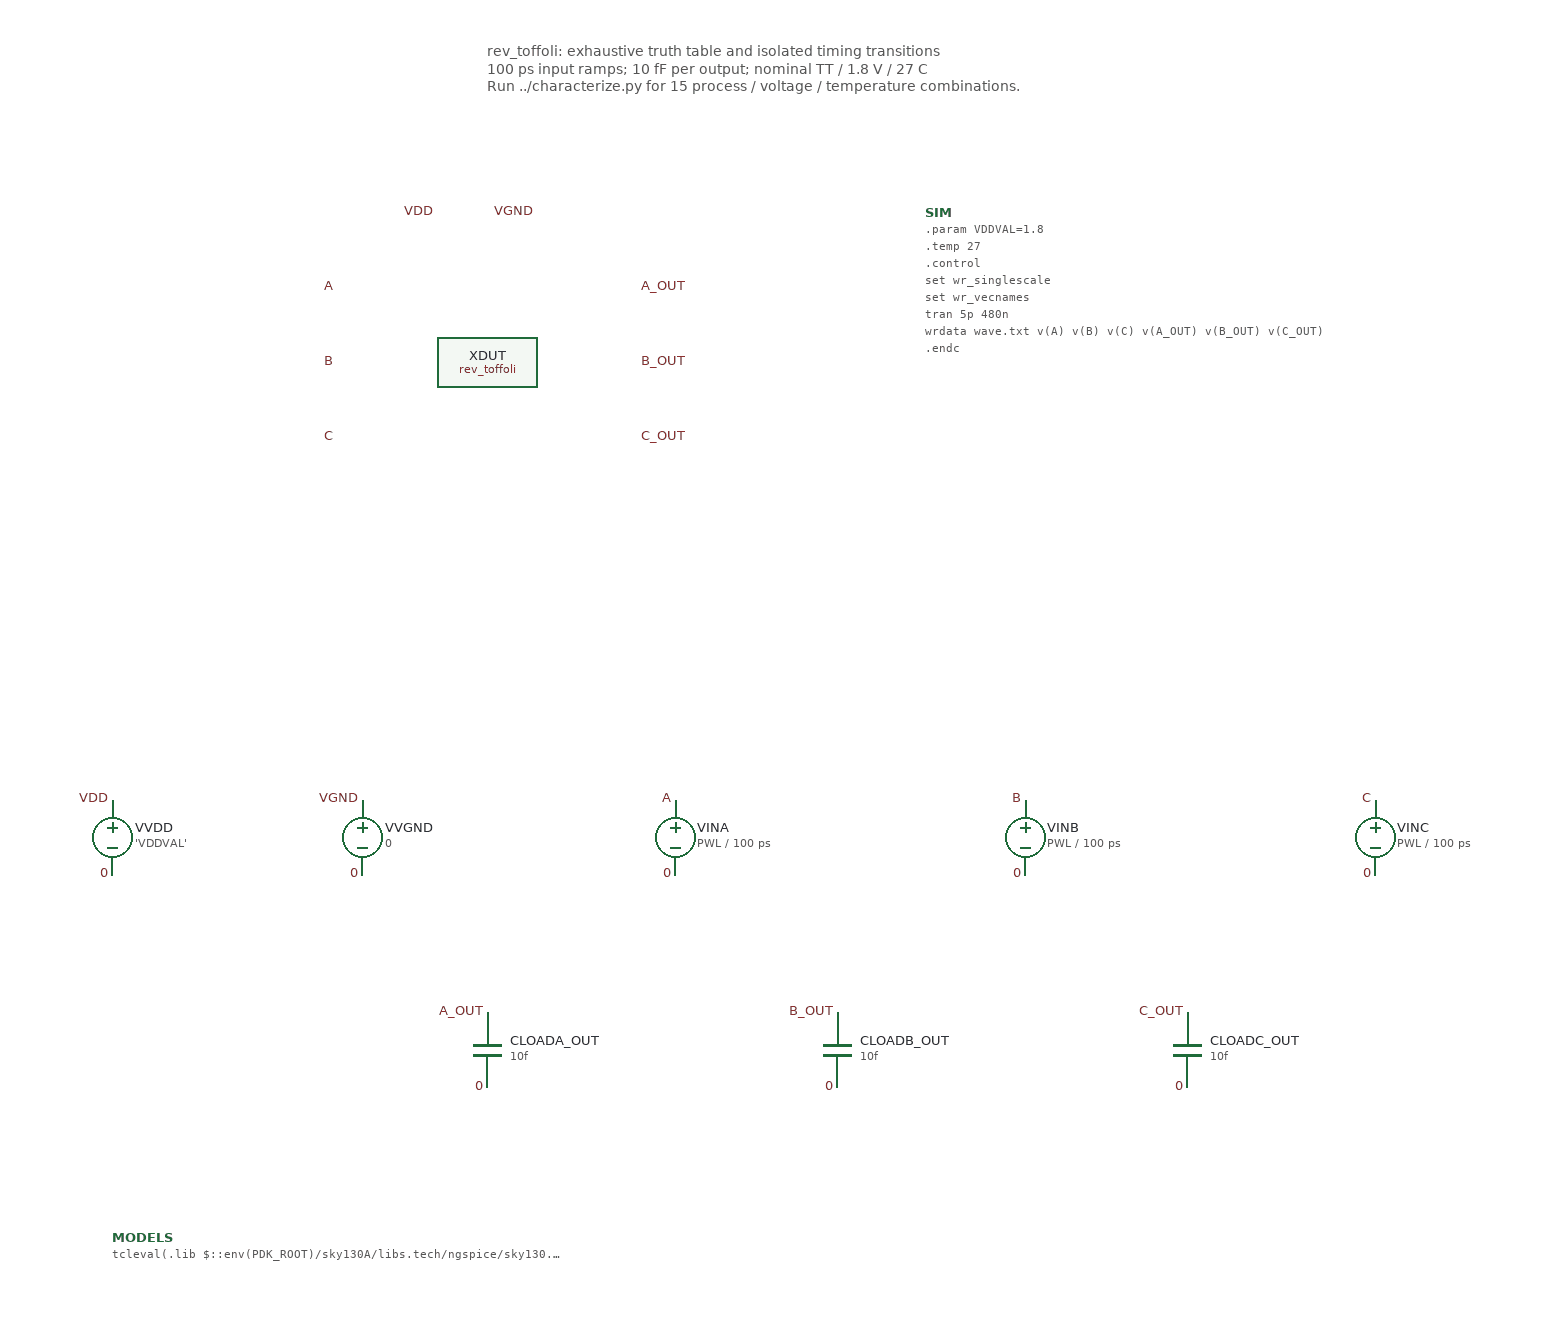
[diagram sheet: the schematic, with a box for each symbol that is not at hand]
v {xschem version=3.4.8RC file_version=1.3}
G {}
K {}
V {}
S {}
E {}
T {rev_toffoli: exhaustive truth table and isolated timing transitions
100 ps input ramps; 10 fF per output; nominal TT / 1.8 V / 27 C
Run ../characterize.py for 15 process / voltage / temperature combinations.} 0 -260 0 0 0.35 0.35 {}
C {rev_toffoli.sym} 0 0 0 0 {name=XDUT}
C {lab_pin.sym} -40 -120 0 0 {name=l-40_-120 sig_type=std_logic lab=VDD}
C {lab_pin.sym} 40 -120 0 0 {name=l40_-120 sig_type=std_logic lab=VGND}
C {lab_pin.sym} -120 -60 0 0 {name=l-120_-60 sig_type=std_logic lab=A}
C {lab_pin.sym} -120 0 0 0 {name=l-120_0 sig_type=std_logic lab=B}
C {lab_pin.sym} -120 60 0 0 {name=l-120_60 sig_type=std_logic lab=C}
C {lab_pin.sym} 120 -60 0 1 {name=l120_-60 lab=A_OUT}
C {lab_pin.sym} 120 0 0 1 {name=l120_0 lab=B_OUT}
C {lab_pin.sym} 120 60 0 1 {name=l120_60 lab=C_OUT}
C {vsource.sym} -300 380 0 0 {name=VVDD value="'VDDVAL'"}
C {lab_pin.sym} -300 350 0 0 {name=l-300_350 sig_type=std_logic lab=VDD}
C {lab_pin.sym} -300 410 0 0 {name=l-300_410 sig_type=std_logic lab=0}
C {vsource.sym} -100 380 0 0 {name=VVGND value="0"}
C {lab_pin.sym} -100 350 0 0 {name=l-100_350 sig_type=std_logic lab=VGND}
C {lab_pin.sym} -100 410 0 0 {name=l-100_410 sig_type=std_logic lab=0}
C {vsource.sym} 150 380 0 0 {name=VINA value="PWL / 100 ps" format="@name @pinlist @stimulus" stimulus="PWL(
+ 0n 'VDDVAL*0'
+ 10n 'VDDVAL*0'
+ 10.1n 'VDDVAL*1'
+ 20n 'VDDVAL*1'
+ 20.1n 'VDDVAL*0'
+ 30n 'VDDVAL*0'
+ 30.1n 'VDDVAL*0'
+ 40n 'VDDVAL*0'
+ 40.1n 'VDDVAL*0'
+ 50n 'VDDVAL*0'
+ 50.1n 'VDDVAL*0'
+ 60n 'VDDVAL*0'
+ 60.1n 'VDDVAL*0'
+ 70n 'VDDVAL*0'
+ 70.1n 'VDDVAL*1'
+ 80n 'VDDVAL*1'
+ 80.1n 'VDDVAL*0'
+ 90n 'VDDVAL*0'
+ 90.1n 'VDDVAL*0'
+ 100n 'VDDVAL*0'
+ 100.1n 'VDDVAL*0'
+ 110n 'VDDVAL*0'
+ 110.1n 'VDDVAL*0'
+ 120n 'VDDVAL*0'
+ 120.1n 'VDDVAL*0'
+ 130n 'VDDVAL*0'
+ 130.1n 'VDDVAL*1'
+ 140n 'VDDVAL*1'
+ 140.1n 'VDDVAL*0'
+ 150n 'VDDVAL*0'
+ 150.1n 'VDDVAL*0'
+ 160n 'VDDVAL*0'
+ 160.1n 'VDDVAL*0'
+ 170n 'VDDVAL*0'
+ 170.1n 'VDDVAL*0'
+ 180n 'VDDVAL*0'
+ 180.1n 'VDDVAL*0'
+ 190n 'VDDVAL*0'
+ 190.1n 'VDDVAL*1'
+ 200n 'VDDVAL*1'
+ 200.1n 'VDDVAL*0'
+ 210n 'VDDVAL*0'
+ 210.1n 'VDDVAL*0'
+ 220n 'VDDVAL*0'
+ 220.1n 'VDDVAL*0'
+ 230n 'VDDVAL*0'
+ 230.1n 'VDDVAL*0'
+ 240n 'VDDVAL*0'
+ 240.1n 'VDDVAL*1'
+ 250n 'VDDVAL*1'
+ 250.1n 'VDDVAL*0'
+ 260n 'VDDVAL*0'
+ 260.1n 'VDDVAL*1'
+ 270n 'VDDVAL*1'
+ 270.1n 'VDDVAL*1'
+ 280n 'VDDVAL*1'
+ 280.1n 'VDDVAL*1'
+ 290n 'VDDVAL*1'
+ 290.1n 'VDDVAL*1'
+ 300n 'VDDVAL*1'
+ 300.1n 'VDDVAL*1'
+ 310n 'VDDVAL*1'
+ 310.1n 'VDDVAL*0'
+ 320n 'VDDVAL*0'
+ 320.1n 'VDDVAL*1'
+ 330n 'VDDVAL*1'
+ 330.1n 'VDDVAL*1'
+ 340n 'VDDVAL*1'
+ 340.1n 'VDDVAL*1'
+ 350n 'VDDVAL*1'
+ 350.1n 'VDDVAL*1'
+ 360n 'VDDVAL*1'
+ 360.1n 'VDDVAL*1'
+ 370n 'VDDVAL*1'
+ 370.1n 'VDDVAL*0'
+ 380n 'VDDVAL*0'
+ 380.1n 'VDDVAL*1'
+ 390n 'VDDVAL*1'
+ 390.1n 'VDDVAL*1'
+ 400n 'VDDVAL*1'
+ 400.1n 'VDDVAL*1'
+ 410n 'VDDVAL*1'
+ 410.1n 'VDDVAL*1'
+ 420n 'VDDVAL*1'
+ 420.1n 'VDDVAL*1'
+ 430n 'VDDVAL*1'
+ 430.1n 'VDDVAL*0'
+ 440n 'VDDVAL*0'
+ 440.1n 'VDDVAL*1'
+ 450n 'VDDVAL*1'
+ 450.1n 'VDDVAL*1'
+ 460n 'VDDVAL*1'
+ 460.1n 'VDDVAL*1'
+ 470n 'VDDVAL*1'
+ 470.1n 'VDDVAL*1')"}
C {lab_pin.sym} 150 350 0 0 {name=l150_350 sig_type=std_logic lab=A}
C {lab_pin.sym} 150 410 0 0 {name=l150_410 sig_type=std_logic lab=0}
C {vsource.sym} 430 380 0 0 {name=VINB value="PWL / 100 ps" format="@name @pinlist @stimulus" stimulus="PWL(
+ 0n 'VDDVAL*0'
+ 10n 'VDDVAL*0'
+ 10.1n 'VDDVAL*0'
+ 20n 'VDDVAL*0'
+ 20.1n 'VDDVAL*0'
+ 30n 'VDDVAL*0'
+ 30.1n 'VDDVAL*1'
+ 40n 'VDDVAL*1'
+ 40.1n 'VDDVAL*0'
+ 50n 'VDDVAL*0'
+ 50.1n 'VDDVAL*0'
+ 60n 'VDDVAL*0'
+ 60.1n 'VDDVAL*0'
+ 70n 'VDDVAL*0'
+ 70.1n 'VDDVAL*0'
+ 80n 'VDDVAL*0'
+ 80.1n 'VDDVAL*0'
+ 90n 'VDDVAL*0'
+ 90.1n 'VDDVAL*1'
+ 100n 'VDDVAL*1'
+ 100.1n 'VDDVAL*0'
+ 110n 'VDDVAL*0'
+ 110.1n 'VDDVAL*0'
+ 120n 'VDDVAL*0'
+ 120.1n 'VDDVAL*1'
+ 130n 'VDDVAL*1'
+ 130.1n 'VDDVAL*1'
+ 140n 'VDDVAL*1'
+ 140.1n 'VDDVAL*1'
+ 150n 'VDDVAL*1'
+ 150.1n 'VDDVAL*0'
+ 160n 'VDDVAL*0'
+ 160.1n 'VDDVAL*1'
+ 170n 'VDDVAL*1'
+ 170.1n 'VDDVAL*1'
+ 180n 'VDDVAL*1'
+ 180.1n 'VDDVAL*1'
+ 190n 'VDDVAL*1'
+ 190.1n 'VDDVAL*1'
+ 200n 'VDDVAL*1'
+ 200.1n 'VDDVAL*1'
+ 210n 'VDDVAL*1'
+ 210.1n 'VDDVAL*0'
+ 220n 'VDDVAL*0'
+ 220.1n 'VDDVAL*1'
+ 230n 'VDDVAL*1'
+ 230.1n 'VDDVAL*1'
+ 240n 'VDDVAL*1'
+ 240.1n 'VDDVAL*0'
+ 250n 'VDDVAL*0'
+ 250.1n 'VDDVAL*0'
+ 260n 'VDDVAL*0'
+ 260.1n 'VDDVAL*0'
+ 270n 'VDDVAL*0'
+ 270.1n 'VDDVAL*1'
+ 280n 'VDDVAL*1'
+ 280.1n 'VDDVAL*0'
+ 290n 'VDDVAL*0'
+ 290.1n 'VDDVAL*0'
+ 300n 'VDDVAL*0'
+ 300.1n 'VDDVAL*0'
+ 310n 'VDDVAL*0'
+ 310.1n 'VDDVAL*0'
+ 320n 'VDDVAL*0'
+ 320.1n 'VDDVAL*0'
+ 330n 'VDDVAL*0'
+ 330.1n 'VDDVAL*1'
+ 340n 'VDDVAL*1'
+ 340.1n 'VDDVAL*0'
+ 350n 'VDDVAL*0'
+ 350.1n 'VDDVAL*0'
+ 360n 'VDDVAL*0'
+ 360.1n 'VDDVAL*1'
+ 370n 'VDDVAL*1'
+ 370.1n 'VDDVAL*1'
+ 380n 'VDDVAL*1'
+ 380.1n 'VDDVAL*1'
+ 390n 'VDDVAL*1'
+ 390.1n 'VDDVAL*0'
+ 400n 'VDDVAL*0'
+ 400.1n 'VDDVAL*1'
+ 410n 'VDDVAL*1'
+ 410.1n 'VDDVAL*1'
+ 420n 'VDDVAL*1'
+ 420.1n 'VDDVAL*1'
+ 430n 'VDDVAL*1'
+ 430.1n 'VDDVAL*1'
+ 440n 'VDDVAL*1'
+ 440.1n 'VDDVAL*1'
+ 450n 'VDDVAL*1'
+ 450.1n 'VDDVAL*0'
+ 460n 'VDDVAL*0'
+ 460.1n 'VDDVAL*1'
+ 470n 'VDDVAL*1'
+ 470.1n 'VDDVAL*1')"}
C {lab_pin.sym} 430 350 0 0 {name=l430_350 sig_type=std_logic lab=B}
C {lab_pin.sym} 430 410 0 0 {name=l430_410 sig_type=std_logic lab=0}
C {vsource.sym} 710 380 0 0 {name=VINC value="PWL / 100 ps" format="@name @pinlist @stimulus" stimulus="PWL(
+ 0n 'VDDVAL*0'
+ 10n 'VDDVAL*0'
+ 10.1n 'VDDVAL*0'
+ 20n 'VDDVAL*0'
+ 20.1n 'VDDVAL*0'
+ 30n 'VDDVAL*0'
+ 30.1n 'VDDVAL*0'
+ 40n 'VDDVAL*0'
+ 40.1n 'VDDVAL*0'
+ 50n 'VDDVAL*0'
+ 50.1n 'VDDVAL*1'
+ 60n 'VDDVAL*1'
+ 60.1n 'VDDVAL*1'
+ 70n 'VDDVAL*1'
+ 70.1n 'VDDVAL*1'
+ 80n 'VDDVAL*1'
+ 80.1n 'VDDVAL*1'
+ 90n 'VDDVAL*1'
+ 90.1n 'VDDVAL*1'
+ 100n 'VDDVAL*1'
+ 100.1n 'VDDVAL*1'
+ 110n 'VDDVAL*1'
+ 110.1n 'VDDVAL*0'
+ 120n 'VDDVAL*0'
+ 120.1n 'VDDVAL*0'
+ 130n 'VDDVAL*0'
+ 130.1n 'VDDVAL*0'
+ 140n 'VDDVAL*0'
+ 140.1n 'VDDVAL*0'
+ 150n 'VDDVAL*0'
+ 150.1n 'VDDVAL*0'
+ 160n 'VDDVAL*0'
+ 160.1n 'VDDVAL*0'
+ 170n 'VDDVAL*0'
+ 170.1n 'VDDVAL*1'
+ 180n 'VDDVAL*1'
+ 180.1n 'VDDVAL*1'
+ 190n 'VDDVAL*1'
+ 190.1n 'VDDVAL*1'
+ 200n 'VDDVAL*1'
+ 200.1n 'VDDVAL*1'
+ 210n 'VDDVAL*1'
+ 210.1n 'VDDVAL*1'
+ 220n 'VDDVAL*1'
+ 220.1n 'VDDVAL*1'
+ 230n 'VDDVAL*1'
+ 230.1n 'VDDVAL*0'
+ 240n 'VDDVAL*0'
+ 240.1n 'VDDVAL*0'
+ 250n 'VDDVAL*0'
+ 250.1n 'VDDVAL*0'
+ 260n 'VDDVAL*0'
+ 260.1n 'VDDVAL*0'
+ 270n 'VDDVAL*0'
+ 270.1n 'VDDVAL*0'
+ 280n 'VDDVAL*0'
+ 280.1n 'VDDVAL*0'
+ 290n 'VDDVAL*0'
+ 290.1n 'VDDVAL*1'
+ 300n 'VDDVAL*1'
+ 300.1n 'VDDVAL*1'
+ 310n 'VDDVAL*1'
+ 310.1n 'VDDVAL*1'
+ 320n 'VDDVAL*1'
+ 320.1n 'VDDVAL*1'
+ 330n 'VDDVAL*1'
+ 330.1n 'VDDVAL*1'
+ 340n 'VDDVAL*1'
+ 340.1n 'VDDVAL*1'
+ 350n 'VDDVAL*1'
+ 350.1n 'VDDVAL*0'
+ 360n 'VDDVAL*0'
+ 360.1n 'VDDVAL*0'
+ 370n 'VDDVAL*0'
+ 370.1n 'VDDVAL*0'
+ 380n 'VDDVAL*0'
+ 380.1n 'VDDVAL*0'
+ 390n 'VDDVAL*0'
+ 390.1n 'VDDVAL*0'
+ 400n 'VDDVAL*0'
+ 400.1n 'VDDVAL*0'
+ 410n 'VDDVAL*0'
+ 410.1n 'VDDVAL*1'
+ 420n 'VDDVAL*1'
+ 420.1n 'VDDVAL*1'
+ 430n 'VDDVAL*1'
+ 430.1n 'VDDVAL*1'
+ 440n 'VDDVAL*1'
+ 440.1n 'VDDVAL*1'
+ 450n 'VDDVAL*1'
+ 450.1n 'VDDVAL*1'
+ 460n 'VDDVAL*1'
+ 460.1n 'VDDVAL*1'
+ 470n 'VDDVAL*1'
+ 470.1n 'VDDVAL*0')"}
C {lab_pin.sym} 710 350 0 0 {name=l710_350 sig_type=std_logic lab=C}
C {lab_pin.sym} 710 410 0 0 {name=l710_410 sig_type=std_logic lab=0}
C {capa.sym} 0 550 0 0 {name=CLOADA_OUT value=10f}
C {lab_pin.sym} 0 520 0 0 {name=l0_520 sig_type=std_logic lab=A_OUT}
C {lab_pin.sym} 0 580 0 0 {name=l0_580 sig_type=std_logic lab=0}
C {capa.sym} 280 550 0 0 {name=CLOADB_OUT value=10f}
C {lab_pin.sym} 280 520 0 0 {name=l280_520 sig_type=std_logic lab=B_OUT}
C {lab_pin.sym} 280 580 0 0 {name=l280_580 sig_type=std_logic lab=0}
C {capa.sym} 560 550 0 0 {name=CLOADC_OUT value=10f}
C {lab_pin.sym} 560 520 0 0 {name=l560_520 sig_type=std_logic lab=C_OUT}
C {lab_pin.sym} 560 580 0 0 {name=l560_580 sig_type=std_logic lab=0}
C {code_shown.sym} 350 -120 0 0 {name=SIM only_toplevel=false value=".param VDDVAL=1.8
.temp 27
.control
set wr_singlescale
set wr_vecnames
tran 5p 480n
wrdata wave.txt v(A) v(B) v(C) v(A_OUT) v(B_OUT) v(C_OUT)
.endc"}
C {code_shown.sym} -300 700 0 0 {name=MODELS only_toplevel=false value="tcleval(.lib $::env(PDK_ROOT)/sky130A/libs.tech/ngspice/sky130.lib.spice tt)"}
